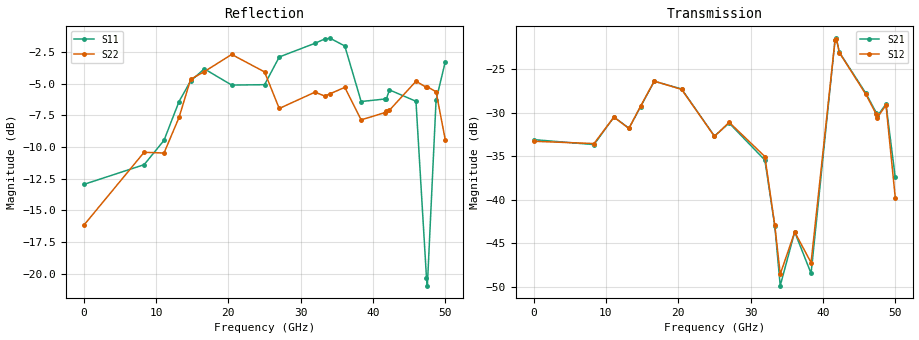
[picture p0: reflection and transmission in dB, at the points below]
!Keysight Technologies,N5245B,MY58422270,A.16.20.02
!Date: Thursday, March 05, 2026 01:46:22
!Correction: S11(C  2-Port  )
!S21(C  2-Port  )
!S12(C  2-Port  )
!S22(C  2-Port  )
!S2P File: Measurements: S11, S21, S12, S22:
# Hz S  dB  R 50
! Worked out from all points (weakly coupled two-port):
!   3201 points, 10 MHz to 50 GHz, reference 50 ohm
!   highest |S21| = -21.48 dB at 41.86 GHz (marker M1); lowest = -49.9 dB at 34.1 GHz (marker M2)
!   lowest |S11| = -20.9 dB at 47.52 GHz (marker M3), VSWR 1.20, Z = 45.9 + j7.56 ohm
!   |S11| at or under -10 dB: start of sweep to 10.13 GHz; 11.32 GHz to 11.95 GHz (633.3 MHz wide, 5.44 % of centre); 46.69 GHz to 48.22 GHz (1.53 GHz wide, 3.22 % of centre)
!   |S22| runs from -20.9 to -2.6 dB; largest |S21 - S12| = 0.0086
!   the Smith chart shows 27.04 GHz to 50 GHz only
!   S11 on the Smith chart (normalised r, x): 27.04 GHz: 0.18, +0.29; 31.97 GHz: 0.39, +1.63; 36.1 GHz: 3.32, -4.15; 42.27 GHz: 1.09, -1.31; 47.39 GHz: 0.85, +0.09; 50 GHz: 0.65, -1.49
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1e7  -12.95 -4.6  -33.10 7.1  -33.29 14.8  -16.18 40.9
8.352081e9  -11.39 176.7  -33.67 33.6  -33.55 33.7  -10.41 -178.3
1.110153e10  -9.47 108.8  -30.51 -57.4  -30.52 -57.8  -10.47 81.9
1.317924e10  -6.40 63.1  -31.79 -109.0  -31.82 -108.7  -7.66 -25.7
1.478829e10  -4.77 11.4  -29.32 -142.8  -29.26 -142.6  -4.64 -90.8
1.667854e10  -3.82 -44.0  -26.40 161.4  -26.39 161.2  -4.04 -139.2
2.045903e10  -5.10 -120.1  -27.29 42.5  -27.33 41.9  -2.68 156.7
2.5005e10  -5.07 -175.4  -32.70 -62.5  -32.73 -62.1  -4.06 72.0
2.703584e10  -2.88 146.5  -31.20 -108.7  -31.11 -108.8  -6.95 34.0
3.197236e10  -1.80 61.0  -35.45 59.2  -35.04 61.6  -5.66 -92.9
3.334708e10  -1.45 35.9  -43.03 0.3  -42.95 -0.2  -5.97 -123.2
3.409693e10  -1.41 22.3  -49.86 -59.7  -48.55 -54.7  -5.78 -137.9
3.609653e10  -2.01 -17.0  -43.70 129.4  -43.70 124.4  -5.28 -175.2
3.83617e10  -6.40 -23.6  -48.45 114.6  -47.22 -94.8  -7.85 145.3
4.167354e10  -6.20 -52.5  -21.66 -51.3  -21.68 -51.2  -7.27 118.4
4.1861e10  -6.18 -52.4  -21.48 -69.6  -21.53 -69.2  -7.11 116.4
4.226717e10  -5.48 -53.9  -23.07 -105.0  -23.11 -104.9  -7.09 113.1
4.593831e10  -6.38 -112.5  -27.78 48.5  -27.91 48.2  -4.80 61.6
4.739115e10  -20.31 146.5  -30.04 -7.1  -30.21 -6.6  -5.28 42.0
4.751612e10  -20.95 114.2  -30.41 -9.6  -30.58 -8.5  -5.24 40.5
4.871901e10  -6.29 -21.1  -29.01 -86.1  -29.13 -86.6  -5.63 16.4
5e10  -3.24 -61.1  -37.44 -121.0  -39.75 -124.9  -9.45 -0.7
